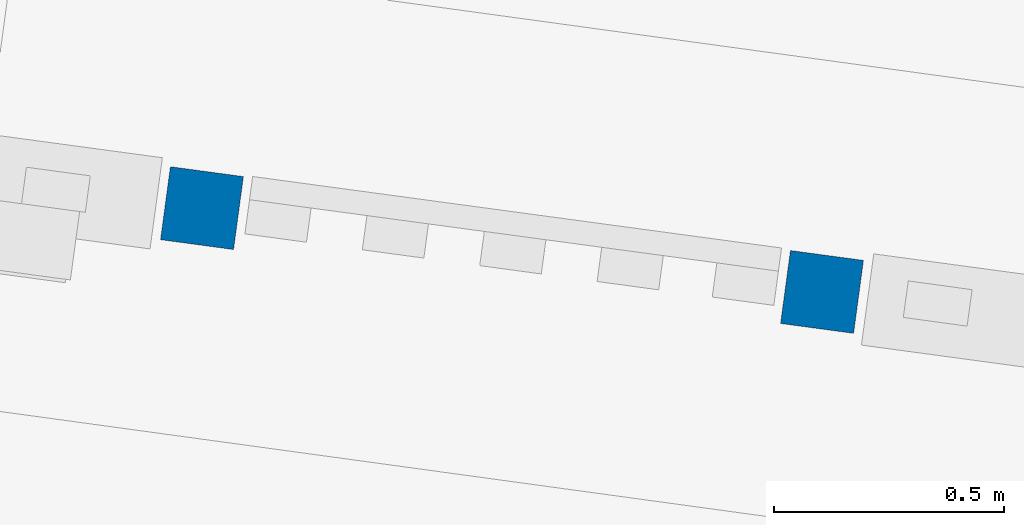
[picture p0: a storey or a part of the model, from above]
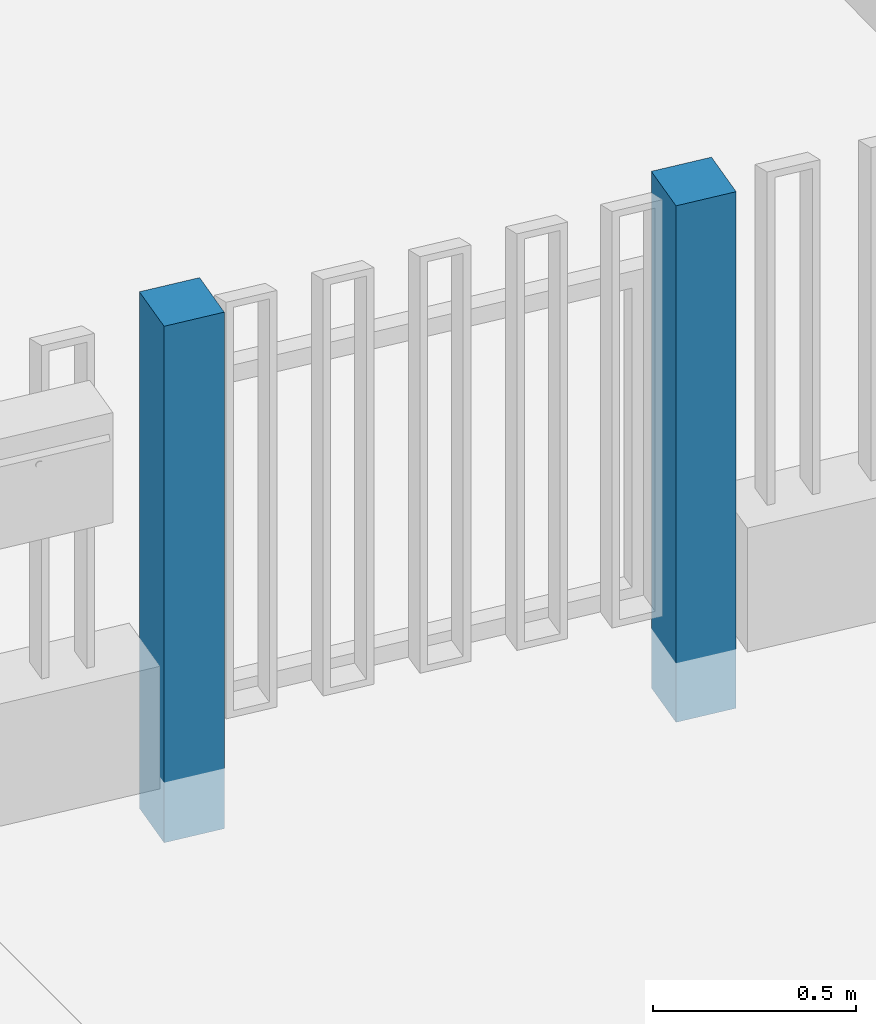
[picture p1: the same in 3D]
Properties of the parts of a building model (IFC2X3)

# File
Description: ViewDefinition [CoordinationView_V2.0]
File name: 1560
Time: 2022-04-13T12:18:16
Written by: The EXPRESS Data Manager Version 5.02.0100.07 : 28 Aug 2013
Made in: 20190808_0900(x64) - Exporter 19.2.20.24 - Alternate UI 19.2.20.24
Comment: STEP Physical File produced by: The EXPRESS Data Manager Version 5.02.0100.07 : 28 Aug 2013 * Module: EDMstepFileFactory/EDMstandAlone * Creation date: Wed Apr 13 12:18:16 2022 * Host: ML790-5 * Database: C:\Users\marti\AppData\Local\Temp\{E913BF59-108C-4111-994B-F60527C21E79}\ifc * Database version: 5507 * Database creation date: Wed Apr 13 12:17:31 2022 * Schema: IFC2X3 * Model: DataRepository.ifc * Model creation date: Wed Apr 13 12:17:31 2022 * Header model: DataRepository.ifc_HeaderModel * Header model creation date: Wed Apr 13 12:17:31 2022 * EDMuser: sdai-user * EDMgroup: sdai-group * License ID and type: 5605 : Permanent license. Expiry date: * EDMstepFileFactory options: 020000

# IfcProject, 1560
LongName: KIVIÕLI ÜHISHOONE; Phase: PÕHIPROJEKT

# IfcSite, Default
RefLatitude: 59, 26, 13, 915100; RefLongitude: 24, 45, 13, 320922; RefElevation: 0 mm

# IfcBuildingStorey (3)
Name | LongName | Elevation (mm)
1. KORRUS | 1. KORRUS | 0
2. KORRUS | 2. KORRUS | 4000
KATUS | KATUS | 8000

# IfcBeam: RHS-Rectangular Hollow Section:80x80 (2)
In: 1. KORRUS
Type - PredefinedType: BEAM
Material: Steel, 45-345
Name (RHS-Rectangular Hollow Section:80x80:...)
3115824
3115979

# IfcBuildingElementProxy: High security automatic bollard M30 (RB348) (14)
In: 1. KORRUS
Type - Material: Metal - Tiso - Galvanized and powder coated, Plastic - Tiso - Painted
Group: Model Group:AS-ABI:3729380
Name (bollard:High security automatic bollard M30 (RB348):...)
3729987
3729988
3729989
3729990
3729991
3729992
3729993
3729994
3729995
3729996
3729997
3729998
3729999
3730000

# IfcBuildingElementProxy: joon10,5, parkimine5m:joon10,5:3730305
In: 1. KORRUS
Type - Material: teekattemärgistus
Group: Model Group:AS-ABI:3729380

# IfcBuildingElementProxy: korvpalli-jooned, korvpalli-jooned:korvpalli-jooned:3730338
In: 1. KORRUS
Type - Material: teekattemärgistus
Group: Model Group:AS-ABI:3729380

# IfcBuildingElementProxy: parkimine5m (32)
In: 1. KORRUS
Type - Material: teekattemärgistus
Name (parkimine5m:parkimine5m:...) | Group
3729959 | Model Group:Array Group 1:3729946
3729960 | Model Group:AS-ABI:3729380
3729961 | Model Group:AS-ABI:3729380
3729962 | Model Group:AS-ABI:3729380
3729963 | Model Group:AS-ABI:3729380
3729964 | Model Group:AS-ABI:3729380
3729965 | Model Group:AS-ABI:3729380
3729966 | Model Group:AS-ABI:3729380
3729967 | Model Group:AS-ABI:3729380
3729968 | Model Group:AS-ABI:3729380
3729969 | Model Group:AS-ABI:3729380
3729970 | Model Group:AS-ABI:3729380
3729971 | Model Group:AS-ABI:3729380
3729972 | Model Group:AS-ABI:3729380
3729973 | Model Group:AS-ABI:3729380
3729974 | Model Group:AS-ABI:3729380
3729975 | Model Group:AS-ABI:3729380
3729977 | Model Group:AS-ABI:3729380
3729978 | Model Group:AS-ABI:3729380
3729979 | Model Group:AS-ABI:3729380
3730045 | Model Group:Array Group 1:3730044
3730047 | Model Group:Array Group 1:3730046
3730049 | Model Group:Array Group 1:3730048
3730051 | Model Group:Array Group 1:3730050
3730053 | Model Group:Array Group 1:3730052
3730055 | Model Group:Array Group 1:3730054
3730300 | Model Group:AS-ABI:3729380
3730301 | Model Group:AS-ABI:3729380
3730302 | Model Group:AS-ABI:3729380
3730303 | Model Group:AS-ABI:3729380
3730304 | Model Group:AS-ABI:3729380
3730337 | Model Group:AS-ABI:3729380

# IfcBuildingElementProxy: prygikast_look-at3, prygikast_look-at3:prygikast_look-at3:3730363
In: 1. KORRUS
Type - Material: roostevaba teras, Default New Material_must-al-komposiitplaat
Group: Model Group:AS-ABI:3729380

# IfcBuildingElementProxy: prygikast_look30, prygikast_look30:prygikast_look30:3730364
In: 1. KORRUS
Type - Material: Default New Material_must-al-komposiitplaat, roostevaba teras
Group: Model Group:AS-ABI:3729380

# IfcBuildingElementProxy: varav-teekate (2)
In: 1. KORRUS
Type - Material: teekattemärgistus
Group: Model Group:AS-ABI:3729380
Name (varav-teekate:varav-teekate:...)
3730203
3730204

# IfcColumn: 150x150x8SHS (3)
In: 1. KORRUS
Type - ElementType: 150x150x8SHS; PredefinedType: COLUMN
Name (teraspost:150x150x8SHS:...) | Material
1441307 | Steel
1441601 | Steel
1441637 | Steel, 45-345

# IfcColumn: 400 x 400mm, r/b post:400 x 400mm:1803355
In: 1. KORRUS
Type - ElementType: 400 x 400mm; PredefinedType: COLUMN
Material: r/b

# IfcColumn: 80x80 (8)
In: 1. KORRUS
Type - ElementType: 80x80; PredefinedType: COLUMN
Material: must (RAL9005)
Name (teraspost:80x80:...)
1866525
1866595
1866724
1866757
1867080
1920232
1920274
1920314

# IfcColumn: Teraspost 160x160 (2)
In: 1. KORRUS
Type - ElementType: Teraspost 160x160; PredefinedType: COLUMN
Material: Default New Material(4); Group: Model Group:AS-ABI:3729380
Name (Columns_Rectangular1:Teraspost 160x160:...)
3730004
3730005

# IfcCovering: Compound Ceiling:varikatus (2)
In: 1. KORRUS
Material: Metal Stud Layer 25 mm, Default New Material_must-al-komposiitplaat -ripplagi 5 mm
Name (Compound Ceiling:varikatus:...)
1458284
1961504

# IfcDiscreteAccessory: 06 meters (3)
In: 1. KORRUS
Type - Material: Default New Material(4)
Group: Model Group:AS-ABI:3729380
Name (M_Flag Pole:06 meters:...)
3730039
3730040
3730041

# IfcDiscreteAccessory: 1200, akna-ylaplekid:1200:2303572
In: 2. KORRUS
Type - Material: Default New Material-must-varv

# IfcDiscreteAccessory: JV3, jalgvarav-kaldu:JV3:3730003
In: 1. KORRUS
Type - Material: Default New Material(4)
Group: Model Group:AS-ABI:3729380

# IfcDiscreteAccessory: Led-ekraani_raam, Led-ekraani_raam1:Led-ekraani_raam:3730354
In: 1. KORRUS
Type - Material: Default New Material-must teras
Group: Model Group:AS-ABI:3729380

# IfcDiscreteAccessory: Reeper, Reeper:Reeper:3729936
In: 1. KORRUS
Group: Model Group:AS-ABI:3729380

# IfcDiscreteAccessory: VV01, Brama skladana V-KING dwuskrzydlowa, nr4801:VV01:3730002
In: 1. KORRUS
Type - Material: logo bk, Default New Material(4), Czarny
Group: Model Group:AS-ABI:3729380

# IfcDiscreteAccessory: VV03, Brama skladana V-KING dwuskrzydlowa, nr4801:VV03:3730001
In: 1. KORRUS
Type - Material: logo bk, Default New Material(4), Czarny
Group: Model Group:AS-ABI:3729380

# IfcDiscreteAccessory: WIùNIOWSKI - PRZEMYSØOWA BRAMA PRZESUWNA 25x25, WIùNIOWSKI - PRZEMYSØOWA BRAMA PRZESUWNA 25x25:WIùNIOWSKI - PRZEMYSØOWA BRAMA PRZESUWNA 25x25:3730306
In: 1. KORRUS
Type - Material: Default New Material(4), logo bk
Group: Model Group:AS-ABI:3729380

# IfcDiscreteAccessory: akna-ylaplekid1000 (44)
Type - Material: Default New Material-must-varv
Name | In
akna-ylaplekid_1k-A:akna-ylaplekid1000:2348102 | 1. KORRUS
akna-ylaplekid_2k-A:akna-ylaplekid1000:2349683 | 1. KORRUS
akna-ylaplekid_2k-A:akna-ylaplekid1000:2349919 | 1. KORRUS
akna-ylaplekid_1k-U:akna-ylaplekid1000:2350845 | 2. KORRUS
akna-ylaplekid_1k-U:akna-ylaplekid1000:2353413 | 2. KORRUS
akna-ylaplekid_1k-U:akna-ylaplekid1000:2353435 | 2. KORRUS
akna-ylaplekid_1k-U:akna-ylaplekid1000:2353622 | 2. KORRUS
akna-ylaplekid_1k-U:akna-ylaplekid1000:2353650 | 2. KORRUS
akna-ylaplekid_1k-U:akna-ylaplekid1000:2353658 | 2. KORRUS
akna-ylaplekid_1k-U:akna-ylaplekid1000:2353686 | 2. KORRUS
akna-ylaplekid_1k-U:akna-ylaplekid1000:2353696 | 2. KORRUS
akna-ylaplekid_1k-U:akna-ylaplekid1000:2353706 | 2. KORRUS
akna-ylaplekid_1k-U:akna-ylaplekid1000:2353714 | 2. KORRUS
akna-ylaplekid_1k-U:akna-ylaplekid1000:2353724 | 2. KORRUS
akna-ylaplekid_1k-U:akna-ylaplekid1000:2353736 | 2. KORRUS
akna-ylaplekid_1k-U:akna-ylaplekid1000:2353766 | 2. KORRUS
akna-ylaplekid_1k-U:akna-ylaplekid1000:2354037 | 2. KORRUS
akna-ylaplekid_1k-U:akna-ylaplekid1000:2354047 | 2. KORRUS
akna-ylaplekid_2k-A:akna-ylaplekid1000:2354082 | 1. KORRUS
akna-ylaplekid_1k-U:akna-ylaplekid1000:2354083 | 2. KORRUS
akna-ylaplekid_1k-U:akna-ylaplekid1000:2354255 | 2. KORRUS
akna-ylaplekid_1k-U:akna-ylaplekid1000:2354263 | 2. KORRUS
akna-ylaplekid_1k-U:akna-ylaplekid1000:2354297 | 2. KORRUS
akna-ylaplekid_1k-U:akna-ylaplekid1000:2354449 | 2. KORRUS
akna-ylaplekid_1k-U:akna-ylaplekid1000:2354490 | 2. KORRUS
akna-ylaplekid_1k-U:akna-ylaplekid1000:2354712 | 2. KORRUS
akna-ylaplekid_1k-U:akna-ylaplekid1000:2354748 | 2. KORRUS
akna-ylaplekid_1k-U:akna-ylaplekid1000:2354764 | 2. KORRUS
akna-ylaplekid_1k-U:akna-ylaplekid1000:2354774 | 2. KORRUS
akna-ylaplekid_2k-A:akna-ylaplekid1000:2354818 | 1. KORRUS
akna-ylaplekid_2k-A:akna-ylaplekid1000:2354994 | 1. KORRUS
akna-ylaplekid_2k-A:akna-ylaplekid1000:2355004 | 1. KORRUS
akna-ylaplekid_2k-U:akna-ylaplekid1000:2356005 | 1. KORRUS
akna-ylaplekid_2k-U:akna-ylaplekid1000:2356177 | 1. KORRUS
akna-ylaplekid_2k-A:akna-ylaplekid1000:2356242 | 1. KORRUS
akna-ylaplekid_2k-U:akna-ylaplekid1000:2356294 | 1. KORRUS
akna-ylaplekid_2k-U:akna-ylaplekid1000:2356380 | 1. KORRUS
akna-ylaplekid_2k-A:akna-ylaplekid1000:2356392 | 1. KORRUS
akna-ylaplekid_2k-U:akna-ylaplekid1000:2356596 | 1. KORRUS
akna-ylaplekid_2k-U:akna-ylaplekid1000:2356629 | 1. KORRUS
akna-ylaplekid_1k-A:akna-ylaplekid1000:2356730 | 1. KORRUS
akna-ylaplekid_1k-A:akna-ylaplekid1000:2356754 | 1. KORRUS
akna-ylaplekid_1k-A:akna-ylaplekid1000:2356764 | 1. KORRUS
akna-ylaplekid_1k-A:akna-ylaplekid1000:2356770 | 1. KORRUS

# IfcDiscreteAccessory: akna-ylaplekid1000 (49)
Type - Material: Must-al-komposiitplaat
Name (akna-ylaplekid:akna-ylaplekid1000:...) | In
2277302 | 2. KORRUS
2278515 | 2. KORRUS
2283995 | 2. KORRUS
2284019 | 2. KORRUS
2284348 | 2. KORRUS
2284439 | 2. KORRUS
2284479 | 2. KORRUS
2284506 | 2. KORRUS
2284533 | 2. KORRUS
2284564 | 2. KORRUS
2284700 | 2. KORRUS
2284730 | 2. KORRUS
2284760 | 2. KORRUS
2284795 | 2. KORRUS
2284805 | 2. KORRUS
2284813 | 2. KORRUS
2284879 | 2. KORRUS
2284887 | 2. KORRUS
2284895 | 2. KORRUS
2284903 | 2. KORRUS
2284911 | 2. KORRUS
2284919 | 2. KORRUS
2284929 | 2. KORRUS
2284937 | 2. KORRUS
2284945 | 2. KORRUS
2284953 | 2. KORRUS
2284961 | 2. KORRUS
2284969 | 2. KORRUS
2284977 | 2. KORRUS
2284985 | 2. KORRUS
2284993 | 2. KORRUS
2285003 | 2. KORRUS
2285089 | 2. KORRUS
2285103 | 2. KORRUS
2285113 | 2. KORRUS
2303062 | 1. KORRUS
2303118 | 1. KORRUS
2303151 | 1. KORRUS
2303161 | 1. KORRUS
2303195 | 1. KORRUS
2303275 | 1. KORRUS
2303283 | 1. KORRUS
2303291 | 1. KORRUS
2303299 | 1. KORRUS
2303307 | 1. KORRUS
2303315 | 1. KORRUS
2303323 | 1. KORRUS
2303407 | 1. KORRUS
2303417 | 1. KORRUS

# IfcDiscreteAccessory: akna-ylaplekid1200 (3)
In: 1. KORRUS
Type - Material: Default New Material-must-varv
Name
akna-ylaplekid_uks120:akna-ylaplekid1200:2358155
akna-ylaplekid_1k-A160:akna-ylaplekid1200:2369087
akna-ylaplekid_1k-A160:akna-ylaplekid1200:2370163

# IfcDiscreteAccessory: akna-ylaplekid1600, akna-ylaplekid_1k-uks:akna-ylaplekid1600:2379663
In: 1. KORRUS
Type - Material: Default New Material-must-varv

# IfcDiscreteAccessory: akna-ylaplekid3600 (6)
In: 1. KORRUS
Type - Material: Default New Material-must-varv
Name
ukse-ylaplekid_3600:akna-ylaplekid3600:2371073
akna-ylaplekid_5400-A:akna-ylaplekid3600:2372717
akna-ylaplekid_5400-A:akna-ylaplekid3600:2373763
akna-ylaplekid_5400-A:akna-ylaplekid3600:2373780
akna-ylaplekid_5400-A:akna-ylaplekid3600:2373802
akna-ylaplekid_5400-A:akna-ylaplekid3600:2373826

# IfcDiscreteAccessory: auto-el-laadija (2)
In: 1. KORRUS
Group: Model Group:AS-ABI:3729380
Name (auto-el-laadija:auto-el-laadija:...)
3730316
3730336

# IfcDiscreteAccessory: hvp-piire (2)
In: 2. KORRUS
Type - Material: Must-al-komposiitplaat
Name (hädaväljapääsu-piire:hvp-piire:...)
1696959
1697348

# IfcDiscreteAccessory: jalarest-suur, jalarest-suur:jalarest-suur:3730215
In: 1. KORRUS
Type - Material: Keevisrest_jalarest
Group: Model Group:AS-ABI:3729380

# IfcDiscreteAccessory: jalgrattahoidja Move 4-osa (2)
In: 1. KORRUS
Type - Material: Default New Material-must teras
Group: Model Group:AS-ABI:3729380
Name
Jalgrattahoidja-move:jalgrattahoidja Move 4-osa:3729976
Jalgrattahoidja-90deg-6:jalgrattahoidja Move 4-osa:3730307

# IfcDiscreteAccessory: korvpall, Korvpallikonstruktsioon_teisaldatav:korvpall:3730389
In: 1. KORRUS
Type - Material: Hoop, Backboard Frame, Net, Glass, Backboard Square, wheels 2, wheels, steel 2, cushion 2, Default, Steel, base
Group: Model Group:AS-ABI:3729380

# IfcDiscreteAccessory: postkast, postkast:postkast:3730390
In: 1. KORRUS
Type - Material: Must-al-komposiitplaat
Group: Model Group:AS-ABI:3729380

# IfcDiscreteAccessory: ukse-pollar (12)
In: 1. KORRUS
Type - Material: Default New Material-must-varv
Name (ukse-pollar:ukse-pollar:...)
2111914
2112768
2112846
2112847
2112859
2112860
2112874
2112875
2112887
2112888
2112959
2113012

# IfcDiscreteAccessory: valguskiri, valguskiri:valguskiri:2673108
In: 2. KORRUS
Type - Material: Default New Material-sinine-valguskast, Default New Material-valge-valguskast

# IfcDoor: GU01_Doors_Industrial_ASSA-ABLOY-OH1042F_With-Passdoor-Low-Threshold_bottom-glazed, Doors_Industrial_ASSA-ABLOY-OH1042F_With-Passdoor-Low-Threshold_bottom-glazed:GU01_Doors_Industrial_ASSA-ABLOY-OH1042F_With-Passdoor-Low-Threshold_bottom-glazed:321510
In: 1. KORRUS
Type - OperationType: SINGLE_SWING_LEFT; ParameterTakesPrecedence: no; Sizeable: no; Classification: B2030 Exterior Doors (Uniformat); Material: ruumivajadus, Steel - Assa Abloy, Default New Material klaas, Default New Material(3), Paint - Assa Abloy - RAL 5010, Paint - Assa Abloy - RAL 9002
Type - Doors_Industrial_ASSA-ABLOY-OH1042F_With-Passdoor-Low-Threshold_bottom-glazed:GU01_Doors_Industrial_ASSA-ABLOY-OH1042F_With-Passdoor-Low-Threshold_bottom-glazed:321510 - PanelOperation: SWINGING
OverallHeight: 4500 mm; OverallWidth: 3600 mm

# IfcDoor: GU01_Doors_Industrial_ASSA-ABLOY-OH1042F_With-Passdoor-Low-Threshold_bottom-glazed (2)
In: 1. KORRUS
Type - OperationType: SINGLE_SWING_LEFT; ParameterTakesPrecedence: no; Sizeable: no; Classification: B2030 Exterior Doors (Uniformat); Material: ruumivajadus, Steel - Assa Abloy, Default New Material klaas, Default New Material(3), Paint - Assa Abloy - RAL 5010, Paint - Assa Abloy - RAL 9002
Type - Doors_Industrial_ASSA-ABLOY-OH1042F_With-Passdoor-Low-Threshold_bottom-glazed:GU01_Doors_Industrial_ASSA-ABLOY-OH1042F_With-Passdoor-Low-Threshold_bottom-glazed:330261 - PanelOperation: SWINGING
OverallHeight: 4500 mm; OverallWidth: 3600 mm
Name (Doors_Industrial_ASSA-ABLOY-OH1042F_With-Passdoor-Low-Threshold_bottom-glazed:GU01_Doors_Industrial_ASSA-ABLOY-OH1042F_With-Passdoor-Low-Threshold_bottom-glazed:...)
330261
330269

# IfcDoor: GU02 (2)
In: 1. KORRUS
Type - ParameterTakesPrecedence: no; Sizeable: no; Classification: B2030410 Overhead Doors (Uniformat); Material: ruumivajadus, Crawford-Steel, Default New Material(3), Default New Material klaas, Tõstuste raamid, RAL9005 (must), Crawford-Black
OverallHeight: 4500 mm; OverallWidth: 3600 mm
Name (Crawford OH1042F-Without Passdoor:GU02:...)
330201
330253

# IfcDoor: GU03_Doors_Industrial_ASSA-ABLOY-OH1042F_With-Passdoor-Low-Threshold, Doors_Industrial_ASSA-ABLOY-OH1042F_With-Passdoor-Low-Threshold:GU03_Doors_Industrial_ASSA-ABLOY-OH1042F_With-Passdoor-Low-Threshold:1631033
In: 1. KORRUS
Type - OperationType: SINGLE_SWING_LEFT; ParameterTakesPrecedence: no; Sizeable: no; Classification: B2030 Exterior Doors (Uniformat); Material: Steel - Assa Abloy, Default Form, Default New Material klaas, Default New Material(3), Paint - Assa Abloy - RAL 9002
Type - Doors_Industrial_ASSA-ABLOY-OH1042F_With-Passdoor-Low-Threshold:GU03_Doors_Industrial_ASSA-ABLOY-OH1042F_With-Passdoor-Low-Threshold:1631033 - PanelOperation: SWINGING
OverallHeight: 3200 mm; OverallWidth: 3600 mm

# IfcDoor: GU04__ASSA-ABLOY-OH1042P, Doors_Industrial_ASSA-ABLOY-OH1042P_Panels-DARP-With-Passdoor:GU04__ASSA-ABLOY-OH1042P:1921022
In: 1. KORRUS
Type - ParameterTakesPrecedence: no; Sizeable: no; Classification: B2030 Exterior Doors (Uniformat); Material: Default New Material-must-varv
OverallHeight: 2375 mm; OverallWidth: 2250 mm

# IfcDoor: GU05_võre-sektsioonuks, Door_Industrail_võrkpaneel:GU05_võre-sektsioonuks:1890043
In: 1. KORRUS
Type - ParameterTakesPrecedence: no; Sizeable: no; Classification: B2030 Exterior Doors (Uniformat); Material: Default New Material-must-varv, venitatud lehtvõrk R1,5/2,5L, must
OverallHeight: 6213.6 mm; OverallWidth: 2590 mm

# IfcDoor: KF1550p-uks-g0,4, kf1550-uks-ebasymmeetriline:KF1550p-uks-g0,4:351626
In: 1. KORRUS
Type - OperationType: DOUBLE_DOOR_SINGLE_SWING; ConstructionType: USERDEFINED; ParameterTakesPrecedence: no; Sizeable: no; Material: Default New Material-al-profiilid, Glass, Clear Glazing
Type - kf1550-uks-ebasymmeetriline:KF1550p-uks-g0,4:351626 - PanelOperation: SWINGING
OverallHeight: 2375 mm; OverallWidth: 1550 mm

# IfcDoor: KFU-2, Uks-KF:KFU-2:1838852
In: 1. KORRUS
Type - OperationType: SINGLE_SWING_RIGHT; ConstructionType: USERDEFINED; ParameterTakesPrecedence: no; Sizeable: no; Material: Default New Material-al-profiilid, Glass
Type - Uks-KF:KFU-2:1838852 - PanelOperation: SWINGING
OverallHeight: 2375 mm; OverallWidth: 1050 mm

# IfcDoor: LU7-1_710x1200mm, uks-1poolne:LU7-1_710x1200mm:507299
In: 2. KORRUS
Type - OperationType: SINGLE_SWING_LEFT; ParameterTakesPrecedence: no; Sizeable: no; Material: Door - Handle, Door - Panel, Door - Frame/Mullion (1)
Type - uks-1poolne:LU7-1_710x1200mm:507299 - PanelOperation: SWINGING
OverallHeight: 1200 mm; OverallWidth: 710 mm

# IfcDoor: VU12-1_1200x3200 (2)
In: 1. KORRUS
Type - ParameterTakesPrecedence: no; Sizeable: no; Material: Default New Material-terasuks-must-varv, Default New Material-al-profiilid, Black_Rubber, Glass, Clear Glazing, Stainless_Steel
OverallHeight: 3200 mm; OverallWidth: 1200 mm
Name (Door_klaas-alumiinium-2p-ebasym-ylaframuug:VU12-1_1200x3200:...)
1563691
1582926

# IfcDoor: VU12-2_1200x3200, Door_klaas-alumiinium-1p-ylaframuug:VU12-2_1200x3200:2142876
In: 1. KORRUS
Type - ParameterTakesPrecedence: no; Sizeable: no; Material: Default New Material-al-profiilid, Black_Rubber, Glass, Clear Glazing, Stainless_Steel
OverallHeight: 3200 mm; OverallWidth: 1200 mm

# IfcDoor: VU12-3_1200x2200, uks_1p:VU12-3_1200x2200:1390836
In: 1. KORRUS
Type - ParameterTakesPrecedence: no; Sizeable: no; Material: must (RAL9005)
OverallHeight: 2200 mm; OverallWidth: 1200 mm

# IfcDoor: VU16-1_1600x3200 EI60, Door_Fuego_Light_EI30_2_Leaf_Type_10_Outward_Opening:VU16-1_1600x3200 EI60:1553727
In: 1. KORRUS
Type - ParameterTakesPrecedence: no; Sizeable: no; Material: Default New Material-al-profiilid, Black_Rubber, Glass, Clear Glazing, Stainless_Steel
OverallHeight: 3200 mm; OverallWidth: 1600 mm

# IfcFlowTerminal: Varikatuse vihmaveetoru 2, Varikatuse vihmaveetoru 3:Varikatuse vihmaveetoru 2:1474822
In: 1. KORRUS
Material: Default New Material(39)

# IfcFlowTerminal: katuselehter (6)
In: KATUS
Material: cast iron
Name (katuse-lehter:katuselehter:...)
1452277
1452550
1452572
1452731
1452732
1452733

# IfcFlowTerminal: restkaev (9)
In: 1. KORRUS
Material: malm; Group: Model Group:AS-ABI:3729380
Name (restkaev:restkaev:...)
3730308
3730309
3730310
3730311
3730312
3730313
3730314
3730315
3730317

# IfcFlowTerminal: trapp (4)
Classification: D2040200 Roof Drains (Uniformat); Material: Platic-WATTS_Polyethylene, Metal-WATTS-Cast Iron
Name (Varikatuse trapp:trapp:...) | In
1454946 | 1. KORRUS
1455447 | 1. KORRUS
1859208 | 2. KORRUS
1860152 | 2. KORRUS

# IfcFlowTerminal: varikatuse vihmaveetoru 1 (4)
In: 1. KORRUS
Name | Material
varikatuse vihmaveetoru 1:varikatuse vihmaveetoru 1:1460412 | Must-al-komposiitplaat
varikatuse vihmaveetoru 4:varikatuse vihmaveetoru 1:1864327 | RAL8023
varikatuse vihmaveetoru 5:varikatuse vihmaveetoru 1:1864361 | RAL8023
varikatuse vihmaveetoru 2:varikatuse vihmaveetoru 1:2538462 | Must-al-komposiitplaat

# IfcGroup: Model Group:Array Group 1 (7)
Group: Model Group:AS-ABI:3729380
Name (Model Group:Array Group 1:...)
3729946
3730044
3730046
3730048
3730050
3730052
3730054

# IfcMember: 50x150mm (6)
In: 1. KORRUS
Type - ElementType: 50x150mm; PredefinedType: MEMBER
Material: Default New Material-al-profiilid
Name (Rectangular Mullion:50x150mm:...)
1839119
1839120
1840244
1840245
1840265
1840273

# IfcMember: 50x200mm (64)
In: 1. KORRUS
Type - ElementType: 50x200mm; PredefinedType: MEMBER
Material: Default New Material-al-profiilid
Name (Rectangular Mullion:50x200mm:...)
351627
351628
351629
351630
351631
351632
351633
351634
351635
351636
351637
351638
351639
351640
351641
351642
351643
351644
351645
351646
351647
351648
351651
351652
351660
351661
351662
351675
351676
351677
351678
351679
351680
351681
351682
351683
351684
351686
351690
351691
351695
351696
351700
351701
351702
351703
351704
351705
351706
351707
2018185
2018186
2018187
2018188
2018189
2018190
2018191
2018192
2018193
2018194
2018195
2018196
2018197
2018244

# IfcPlate: kf-klaaspakett (13)
In: 1. KORRUS
Type - ElementType: kf-klaaspakett; PredefinedType: CURTAIN_PANEL; Material: <Unnamed> 52.8 mm
Name (System Panel:kf-klaaspakett:...)
351614
351698
351693
351688
351616
351618
351620
351622
351650
351624
351654
351672
1840239

# IfcPlate: võrkpaneel (12)
In: 1. KORRUS
Type - ElementType: võrkpaneel; PredefinedType: CURTAIN_PANEL; Material: venitatud lehtvõrk R1,5/2,5L, must, teras, võrkpaneeli raam
Name (võrkpaneel:võrkpaneel:...)
3127803
3127810
3127812
3128598
3128599
3128600
3129706
3129713
3130144
3130147
3129846
3129847

# IfcRailing: Railing:1.2m (3)
In: 1. KORRUS
Material: Default New Material(4); Group: Model Group:AS-ABI:3729380
Name (Railing:1.2m:...)
3729949
3730031
3730036

# IfcRailing: Railing:2m 1 kaar (5)
In: 1. KORRUS
Material: Default New Material(4); Group: Model Group:AS-ABI:3729380
Name (Railing:2m 1 kaar:...)
3730118
3730371
3730376
3730381
3730386

# IfcRailing: Railing:2m 3 (5)
In: 1. KORRUS
Material: Default New Material(4); Group: Model Group:AS-ABI:3729380
Name (Railing:2m 3:...)
3729953
3730013
3730020
3730026
3730333

# IfcRoof: Basic Roof:KL-1 vastukalded:1634265 (8)
In: KATUS
Material: Soojusisolatsioon jäik mineraalvill
Name (Basic Roof:KL-1 vastukalded:...)
1634247
1634482
1634501
1634654
1634694
1634713
1650174
2007985

# IfcRoof: Basic Roof:KL-1:1618662 (5)
In: KATUS
Material: Soojusisolatsioon EPS
Name (Basic Roof:KL-1:...)
1618405
1619995
1620880
1621017
1621148

# IfcRoof: Basic Roof:KL-2:1462136 (5)
In: KATUS
Material: Soojusisolatsioon EPS
Name (Basic Roof:KL-2:...)
684344
1628051
1628784
1629025
1629111

# IfcRoof: Basic Roof:varjualune_pvc-eps:1860663 (7)
In: 2. KORRUS
Material: Soojusisolatsioon EPS
Name (Basic Roof:varjualune_pvc-eps:...)
1859308
1860848
1861051
1863169
1863360
1863862
1864120

# IfcSlab: Basic Roof:varikatus_al (2)
In: 1. KORRUS
PredefinedType: ROOF; Material: Õhkvahe- hor roovid 20 mm, Must-al-komposiitplaat 4 mm
Name (Basic Roof:varikatus_al:...)
422369
422497

# IfcSlab: Basic Roof:varikatus_al yleval (2)
In: 1. KORRUS
PredefinedType: ROOF; Material: Must-al-komposiitplaat 4 mm, Õhkvahe- hor roovid 20 mm
Name (Basic Roof:varikatus_al yleval:...)
2378581
2717406

# IfcSlab: Basic Roof:varikatus_pvc-betoon (6)
In: 1. KORRUS
PredefinedType: ROOF; Material: pvc-katusekate 5 mm, r/b 220 mm

# IfcSlab: Basic Roof:varikatus_pvc-vastukalle (3)
In: 1. KORRUS
PredefinedType: ROOF; Material: pvc-katusekate 5 mm, r/b 35 mm
Name (Basic Roof:varikatus_pvc-vastukalle:...)
1460860
2021885
2507245

# IfcSlab: Floor:Asfalt (2)
In: 1. KORRUS
PredefinedType: FLOOR; Group: Model Group:AS-ABI:3729380
Name (Floor:Asfalt:...)
3730065 | Material: .Asfalt a
3730091

# IfcSlab: Floor:Muru (25)
In: 1. KORRUS
Group: Model Group:AS-ABI:3729380
Name (Floor:Muru:...)
3730058 | PredefinedType: FLOOR; Material: .Muru
3730110 | PredefinedType: FLOOR
9 x 3730136
8 x 3730150
3730159 | PredefinedType: FLOOR
3730166 | PredefinedType: FLOOR
4 x 3730173

# IfcSlab: Floor:Muru-ymbrus (21)
In: 1. KORRUS
Group: Model Group:AS-ABI:3729380
Name (Floor:Muru-ymbrus:...)
11 x 3730180
4 x 3730188
6 x 3730196

# IfcSlab: Floor:PP-1 serv (6)
In: 1. KORRUS
PredefinedType: FLOOR; Material: r/b 200 mm
Name (Floor:PP-1 serv:...)
2603256
2603351
2603376
2603405
2603432
2603472

# IfcSlab: Floor:PP-10_rb150 (6)
In: 1. KORRUS
Name (Floor:PP-10_rb150:...)
4 x 626355
1719830 | PredefinedType: FLOOR; Material: r/b 150 mm, killustik 200 mm
3103832 | PredefinedType: FLOOR; Material: r/b 150 mm, killustik 200 mm

# IfcSlab: Floor:Tartaankate, Floor:Tartaankate:3729982
In: 1. KORRUS
PredefinedType: FLOOR; Material: Tartaankate; Group: Model Group:AS-ABI:3729380

# IfcSlab: Floor:VL-3, Floor:VL-3:490844
In: 2. KORRUS
PredefinedType: FLOOR; Material: Soojusisolatsioon PIR 150 mm

# IfcSlab: Floor:betoonkivisillutis (5)
In: 1. KORRUS
Group: Model Group:AS-ABI:3729380
Name (Floor:betoonkivisillutis:...)
3729942 | PredefinedType: FLOOR; Material: Site - betoonkivi, Liiv, killustik
3730129 | PredefinedType: FLOOR
3 x 3730393

# IfcSlab: Floor:pir-fooliumkattega, Floor:pir-fooliumkattega:2332688
In: 2. KORRUS
PredefinedType: FLOOR; Material: Soojusisolatsioon PIR fooliumkattega 150 mm

# IfcSlab: Floor:pir-paneel100 (6)
PredefinedType: FLOOR; Material: Soojusisolatsioon PIR fooliumkattega 100 mm
Name (Floor:pir-paneel100:...) | In
2475390 | 2. KORRUS
2475390:2 | 2. KORRUS
2475390:3 | 2. KORRUS
2475609 | 1. KORRUS
2475609:2 | 1. KORRUS
2475609:3 | 1. KORRUS

# IfcSlab: Floor:taldmik (6)
In: 1. KORRUS
PredefinedType: FLOOR; Material: r/b 200 mm; Group: Model Group:AS-ABI:3729380
Name (Floor:taldmik:...)
3730273
3730273:2
3730273:3
3730273:4
3730320
3730320:2

# IfcSlab: Floor:äärekivi (35)
In: 1. KORRUS
Group: Model Group:AS-ABI:3729380
Name (Floor:äärekivi:...)
8 x 3730223
7 x 3730231
10 x 3730240
3 x 3730255
7 x 3730262

# IfcWall: Basic Wall:VS-1-tume (4)
In: 1. KORRUS
Type - Material: RECKLI 1 173 THUR by Polantis 2016-tume 100 mm, Soojusisolatsioon EPS 200 mm, r/b 150 mm
Name (Basic Wall:VS-1-tume:...)
1994967 | Material: RECKLI 1 173 THUR by Polantis 2016-tume, Soojusisolatsioon EPS, r/b
1997072
1997203
1997409

# IfcWall: Basic Wall:VS-1_toon-b, Basic Wall:VS-1_toon-b:2001616
In: 1. KORRUS
Type - PredefinedType: STANDARD; Material: RECKLI 1 173 THUR by Polantis 2016-toon3 100 mm, Soojusisolatsioon EPS 200 mm, r/b 150 mm

# IfcWall: Basic Wall:Varikatuse raudbetoontoed (2)
In: 1. KORRUS
Type - Material: Default New Material(1)toed 200 mm
Name (Basic Wall:Varikatuse raudbetoontoed:...)
349691 | Material: Default New Material(1)toed
392899 | Group: Model Group:Group 3:392918

# IfcWallStandardCase: Basic Wall:Aed (8)
In: 1. KORRUS
Type - PredefinedType: STANDARD; Material: aia r/b sokkel 200 mm
Group: Model Group:AS-ABI:3729380
Name (Basic Wall:Aed:...)
3729938
3729939
3730006
3730007
3730008
3730009
3730010
3730115

# IfcWallStandardCase: Basic Wall:Aed-madal (4)
In: 1. KORRUS
Type - PredefinedType: STANDARD; Material: aia r/b sokkel 200 mm
Group: Model Group:AS-ABI:3729380
Name (Basic Wall:Aed-madal:...)
3729937
3729956
3729957
3730042

# IfcWallStandardCase: Basic Wall:Alumiinium-komposiitplaat roovidel (8)
In: 1. KORRUS
Type - PredefinedType: STANDARD; Material: Must-al-komposiitplaat 5 mm, Metal Stud Layer 95 mm
Name (Basic Wall:Alumiinium-komposiitplaat roovidel:...)
385184
1390495
1473416
1640189
1640208
1845179
1857107
1864425

# IfcWallStandardCase: Basic Wall:SS-2 Columbia190 EI30_must, Basic Wall:SS-2 Columbia190 EI30_must:614180
In: 1. KORRUS
Type - PredefinedType: STANDARD; Material: Columbia-kivi(_värvitud-must 190 mm

# IfcWallStandardCase: Basic Wall:VS-1 koorik, Basic Wall:VS-1 koorik:2672658
In: 1. KORRUS
Type - PredefinedType: STANDARD; Material: RECKLI 1 173 THUR by Polantis 2016-toon2 100 mm

# IfcWallStandardCase: Basic Wall:VS-10_R/B200 varjualune, Basic Wall:VS-10_R/B200 varjualune:1866265
In: 1. KORRUS
Type - PredefinedType: STANDARD; Material: r/b 200 mm

# IfcWallStandardCase: Basic Wall:VS-10_rb200_terracota, Basic Wall:VS-10_rb200_terracota:424286
In: 1. KORRUS
Type - PredefinedType: STANDARD; Material: RECKLI 1 173 THUR by Polantis 2016-toon3 30 mm, Default New Material(1) 170 mm

# IfcWallStandardCase: Basic Wall:VS-11_Columbia190 al-komp, Basic Wall:VS-11_Columbia190 al-komp:1857339
In: 1. KORRUS
Type - PredefinedType: STANDARD; Material: Columbia-kivi(_värvitud-must 190 mm

# IfcWallStandardCase: Basic Wall:VS-11_Columbia190 must (2)
In: 1. KORRUS
Type - PredefinedType: STANDARD; Material: Columbia-kivi(_värvitud-must 190 mm
Name (Basic Wall:VS-11_Columbia190 must:...)
1920916
1921017

# IfcWallStandardCase: Basic Wall:VS-11_Columbia240-must, Basic Wall:VS-11_Columbia240-must:385182
In: 1. KORRUS
Type - PredefinedType: STANDARD; Material: Columbia-kivi(_värvitud-must 240 mm

# IfcWallStandardCase: Basic Wall:VS-11_puitvooder (4)
In: 1. KORRUS
Type - PredefinedType: STANDARD; Material: Default New Material-must puit 21 mm, Default New Material-must puit_roov 45 mm
Name (Basic Wall:VS-11_puitvooder:...)
614094
614133
2618603
2618751

# IfcWallStandardCase: Basic Wall:VS-1_toon-a (13)
Type - PredefinedType: STANDARD; Material: RECKLI 1 173 THUR by Polantis 2016-toon4 100 mm, Soojusisolatsioon EPS 200 mm, r/b 150 mm
Name (Basic Wall:VS-1_toon-a:...) | In
1480041 | 1. KORRUS
1493785 | 1. KORRUS
1494873 | 1. KORRUS
1495073 | 1. KORRUS
1847569 | 2. KORRUS
1995693 | 2. KORRUS
1997636 | 1. KORRUS
1999254 | 2. KORRUS
1999788 | 2. KORRUS
2001341 | 2. KORRUS
2001418 | 1. KORRUS
2003019 | 2. KORRUS
2004800 | 2. KORRUS

# IfcWallStandardCase: Basic Wall:VS-1_toon-b (11)
Type - PredefinedType: STANDARD; Material: RECKLI 1 173 THUR by Polantis 2016-toon3 100 mm, Soojusisolatsioon EPS 200 mm, r/b 150 mm
Name (Basic Wall:VS-1_toon-b:...) | In
1493599 | 1. KORRUS
1997878 | 1. KORRUS
1999029 | 2. KORRUS
2001024 | 1. KORRUS
2001534 | 1. KORRUS
2002558 | 2. KORRUS
2002773 | 2. KORRUS
2003366 | 2. KORRUS
2004592 | 2. KORRUS
2004862 | 2. KORRUS
2005035 | 2. KORRUS

# IfcWallStandardCase: Basic Wall:VS-1_toon-c (11)
Type - PredefinedType: STANDARD; Material: RECKLI 1 173 THUR by Polantis 2016-toon2 100 mm, Soojusisolatsioon EPS 200 mm, r/b 150 mm
Name (Basic Wall:VS-1_toon-c:...) | In
1988482 | 1. KORRUS
1998188 | 1. KORRUS
2000551 | 1. KORRUS
2000885 | 1. KORRUS
2002236 | 2. KORRUS
2002379 | 2. KORRUS
2003647 | 2. KORRUS
2003835 | 2. KORRUS
2004212 | 2. KORRUS
2004368 | 2. KORRUS
3183302 | 2. KORRUS

# IfcWallStandardCase: Basic Wall:VS-1_toon-d (7)
Type - PredefinedType: STANDARD; Material: RECKLI 1 173 THUR by Polantis 2016-toon1 100 mm, Soojusisolatsioon EPS 200 mm, r/b 150 mm
Name (Basic Wall:VS-1_toon-d:...) | In
1494532 | 1. KORRUS
1998489 | 1. KORRUS
1998642 | 1. KORRUS
2000146 | 2. KORRUS
2000329 | 2. KORRUS
2003952 | 2. KORRUS
3182995 | 2. KORRUS

# IfcWallStandardCase: Basic Wall:VS-2 -toon-d (5)
Type - PredefinedType: STANDARD; Material: RECKLI 1 173 THUR by Polantis 2016-toon1 100 mm, Soojusisolatsioon PIR 150 mm, r/b 200 mm
Name (Basic Wall:VS-2 -toon-d:...) | In
1615523 | 1. KORRUS
1799124 | 2. KORRUS
1996627 | 1. KORRUS
1998714 | 1. KORRUS
2002087 | 2. KORRUS

# IfcWallStandardCase: Basic Wall:VS-4 (6)
In: 2. KORRUS
Type - PredefinedType: STANDARD; Material: Soojusisolatsioon PIR fooliumkattega 100 mm
Name (Basic Wall:VS-4:...)
2416217
2475674
2475710
2475751
2475797
2475798

# IfcWallStandardCase: Basic Wall:VS-KF yleval, Basic Wall:VS-KF yleval:2622638
In: 1. KORRUS
Type - PredefinedType: STANDARD; Material: Soojusisolatsioon 195 mm

# IfcWallStandardCase: Basic Wall:ekraan, Basic Wall:ekraan:3729958
In: 1. KORRUS
Type - PredefinedType: STANDARD; Material: ekraan 600 mm
Group: Model Group:AS-ABI:3729380

# IfcWallStandardCase: Basic Wall:komposiitplaat+karkass25 (8)
In: 1. KORRUS
Type - PredefinedType: STANDARD; Material: Must-al-komposiitplaat 5 mm, Metal Stud Layer 25 mm
Name (Basic Wall:komposiitplaat+karkass25:...)
1856246
1856282
1856403
1856428
1857160
1857205
1866831
1921313

# IfcWallStandardCase: Basic Wall:parapetid-B_roov100+vineer10 (6)
In: KATUS
Type - PredefinedType: STANDARD; Material: pvc-katusekate 5 mm, vineer niiskuskindel 10 mm, EST. Sügavimmutatud puitroov. parapetid 100 mm
Name (Basic Wall:parapetid-B_roov100+vineer10:...)
2338856
2341920
2342047
2342154
2342225
2342342

# IfcWallStandardCase: Basic Wall:varikatuse serv (8)
Type - PredefinedType: STANDARD; Material: Must-al-komposiitplaat 5 mm, Õhkvahe- hor roovid 20 mm, Õhkvahe- vert roovid 100 mm, Vineer 15 mm
Name (Basic Wall:varikatuse serv:...) | In
1458112 | 1. KORRUS
1458147 | 1. KORRUS
1458214 | 1. KORRUS
1847355 | 1. KORRUS
1859480 | 2. KORRUS
1859865 | 2. KORRUS
1859907 | 2. KORRUS
1859956 | 2. KORRUS

# IfcWallStandardCase: Basic Wall:varikatuse serv20+4 (5)
In: 1. KORRUS
Type - PredefinedType: STANDARD; Material: Must-al-komposiitplaat 4 mm, Õhkvahe- hor roovid 18 mm
Name (Basic Wall:varikatuse serv20+4:...)
2379015
2379067
2394133
2394134
2394320

# IfcWallStandardCase: Basic Wall:vs-tsementkiudplaat (2)
In: 1. KORRUS
Type - PredefinedType: STANDARD; Material: tsementkiudplaat 10 mm
Name (Basic Wall:vs-tsementkiudplaat:...)
1844499
1844644

# IfcWallStandardCase: Basic Wall:vs_mineraalvill 200mm (3)
Type - PredefinedType: STANDARD; Material: Soojusisolatsioon PIR tuletõkkekattega 200 mm
Name (Basic Wall:vs_mineraalvill 200mm:...) | In
1845280 | 1. KORRUS
3183063 | 2. KORRUS
3183452 | 2. KORRUS

# IfcWindow: 1000x2700 (3)
In: 2. KORRUS
Type - ParameterTakesPrecedence: no; Sizeable: no; Material: Aluminium_ALUPROF_black, Default New Material-must puit, Default New Material-must-varv, must
OverallHeight: 2900 mm; OverallWidth: 1200 mm
Name (vent-rest:1000x2700:...)
692012
696308
696352

# IfcWindow: 1127x660, vent-rest2:1127x660:2103898
In: 1. KORRUS
Type - ParameterTakesPrecedence: no; Sizeable: no; Material: must, Default New Material-al-profiilid
OverallHeight: 660 mm; OverallWidth: 1127 mm

# IfcWindow: 2400x660, vent-rest2:2400x660:2104072
In: 1. KORRUS
Type - ParameterTakesPrecedence: no; Sizeable: no; Material: must, Default New Material-al-profiilid
OverallHeight: 660 mm; OverallWidth: 2400 mm

# IfcWindow: A10-1 RC3 (14)
In: 1. KORRUS
Type - ParameterTakesPrecedence: no; Sizeable: no; Material: Aluminium_ALUPROF_black, Glass_ALUPROF_Clear, Glass, Clear Glazing, ExpandingFoam_ALUPROF_Yellow
OverallWidth: 1000 mm
Name (Aluprof_MB-86-SI_E_Alu_Window-1sash-Tilt-and-turn_ENG_R-00044:A10-1 RC3:...) | OverallHeight (mm)
350084 | 2827.54
350085 | 2827.54
350086 | 2827.54
350087 | 2827.54
387296 | 2776.97
387424 | 2827.54
387493 | 2776.97
387513 | 2776.97
387549 | 2776.97
387550 | 2776.97
387617 | 2776.97
387659 | 2827.54
387693 | 2827.54
387737 | 2827.54

# IfcWindow: A10-2 kaldavatav (24)
In: 2. KORRUS
Type - ParameterTakesPrecedence: no; Sizeable: no; Material: Aluminium_ALUPROF_black, Glass_ALUPROF_Clear, Glass, Clear Glazing, ExpandingFoam_ALUPROF_Yellow
OverallWidth: 1000 mm
Name (Aluprof_MB-86-SI_E_Alu_Window-1sash-Tilt-and-turn_ENG_R-00044:A10-2 kaldavatav:...) | OverallHeight (mm)
350095 | 2776.97
350096 | 2776.97
350097 | 2776.97
350098 | 2776.97
350099 | 2776.97
350100 | 2776.97
350101 | 2776.97
350102 | 2776.97
350104 | 2827.54
350105 | 2827.54
350106 | 2827.54
356683 | 2827.54
356746 | 2776.97
356809 | 2827.54
357010 | 2827.54
357136 | 2827.54
357267 | 2827.54
357329 | 2827.54
357330 | 2827.54
357351 | 2827.54
357352 | 2827.54
357387 | 2827.54
357396 | 2827.54
387786 | 2827.54

# IfcWindow: A10-3 kald-pöördavatav (10)
In: 2. KORRUS
Type - ParameterTakesPrecedence: no; Sizeable: no; Material: Aluminium_ALUPROF_black, Glass_ALUPROF_Clear, Glass, Clear Glazing, ExpandingFoam_ALUPROF_Yellow
OverallWidth: 1000 mm
Name (Aluprof_MB-86-SI_E_Alu_Window-1sash-Tilt-and-turn_ENG_R-00044:A10-3 kald-pöördavatav:...) | OverallHeight (mm)
350089 | 2776.97
350090 | 2776.97
350091 | 2776.97
350092 | 2776.97
350093 | 2776.97
350094 | 2776.97
350107 | 2827.54
356599 | 2827.54
628344 | 2776.97
628352 | 2776.97

# IfcWindow: A10-4 ei60, Aluprof_MB-86-SI_E_Alu_Window-1sash-Tilt-and-turn_ENG_R-00044:A10-4 ei60:357070
In: 2. KORRUS
Type - ParameterTakesPrecedence: no; Sizeable: no; Material: Aluminium_ALUPROF_black, Glass_ALUPROF_Clear, Glass, Clear Glazing, ExpandingFoam_ALUPROF_Yellow
OverallHeight: 2827.54 mm; OverallWidth: 1000 mm

# IfcWindow: A12-1, Aluprof_MB-86-SI_E_Alu_Window-1sash-Tilt-and-turn_ENG_R-00044:A12-1:2109330
In: 2. KORRUS
Type - ParameterTakesPrecedence: no; Sizeable: no; Material: Aluminium_ALUPROF_black, Glass_ALUPROF_Clear, Glass, Clear Glazing, ExpandingFoam_ALUPROF_Yellow
OverallHeight: 2776.97 mm; OverallWidth: 1200 mm

# IfcWindow: SL01_suitsuluuk 1200x1200 (7)
In: KATUS
Type - ParameterTakesPrecedence: no; Sizeable: no; Material: akrüül-klaas, 3-kihiline, soojustatud teras-jalam
OverallWidth: 1496.44 mm
Name (Suitsueemaldusluuk:SL01_suitsuluuk 1200x1200:...) | OverallHeight (mm)
685250 | 1336.1
711325 | 1436.1
711458 | 1306.1
712057 | 1306.1
712085 | 1306.1
712675 | 1306.1
1643293 | 1436.1

# IfcWindow: SL02_suitsuluuk 1200x1200 katuselepääs, Suitsueemaldusluuk:SL02_suitsuluuk 1200x1200 katuselepääs:685151
In: KATUS
Type - ParameterTakesPrecedence: no; Sizeable: no; Material: akrüül-klaas, 3-kihiline, soojustatud teras-jalam
OverallHeight: 1311.1 mm; OverallWidth: 1496.44 mm

# IfcWindow: alumiiniumaken, KF-aken:alumiiniumaken:2018156
In: 1. KORRUS
Type - ParameterTakesPrecedence: no; Sizeable: no; Material: Glass, Clear Glazing, must (RAL9005)
OverallHeight: 1300.02 mm; OverallWidth: 925.02 mm
